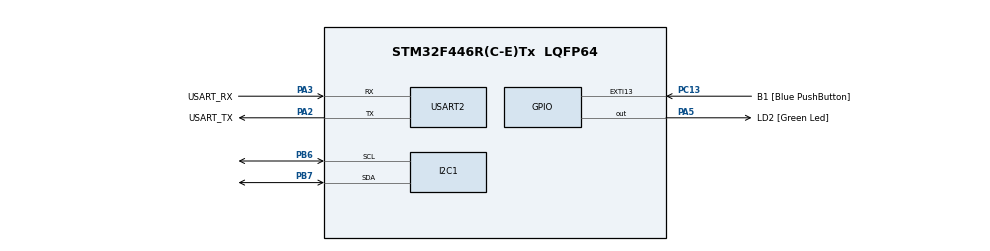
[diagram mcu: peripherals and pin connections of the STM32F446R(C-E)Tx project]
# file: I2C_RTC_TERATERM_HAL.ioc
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Mcu.Family=STM32F4
Mcu.Name=STM32F446R(C-E)Tx
Mcu.Package=LQFP64
NVIC.PriorityGroup=NVIC_PRIORITYGROUP_0
PA13.GPIO_Label=TMS
PA13.Mode=Serial_Wire
PA13.Signal=SYS_JTMS-SWDIO
PA14.GPIO_Label=TCK
PA14.Mode=Serial_Wire
PA14.Signal=SYS_JTCK-SWCLK
PA2.GPIO_Label=USART_TX
PA2.Mode=Asynchronous
PA2.Signal=USART2_TX
PA3.GPIO_Label=USART_RX
PA3.Mode=Asynchronous
PA3.Signal=USART2_RX
PA5.GPIO_Label=LD2 [Green Led]
PA5.Signal=GPIO_Output
PB3.GPIO_Label=SWO
PB3.Signal=SYS_JTDO-SWO
PB6.Mode=I2C
PB6.Signal=I2C1_SCL
PB7.Mode=I2C
PB7.Signal=I2C1_SDA
PC13.GPIO_Label=B1 [Blue PushButton]
PC13.GPIO_ModeDefaultEXTI=GPIO_MODE_IT_FALLING
PC13.Signal=GPXTI13
PC14-OSC32_IN.Mode=LSE-External-Oscillator
PC14-OSC32_IN.Signal=RCC_OSC32_IN
PC15-OSC32_OUT.Mode=LSE-External-Oscillator
PC15-OSC32_OUT.Signal=RCC_OSC32_OUT
PH0-OSC_IN.Mode=HSE-External-Oscillator
PH0-OSC_IN.Signal=RCC_OSC_IN
PH1-OSC_OUT.Mode=HSE-External-Oscillator
PH1-OSC_OUT.Signal=RCC_OSC_OUT
ProjectManager.HeapSize=0x200
ProjectManager.StackSize=0x400
ProjectManager.TargetToolchain=STM32CubeIDE
RCC.48MHZClocksFreq_Value=84000000
RCC.AHBFreq_Value=16000000
RCC.APB1CLKDivider=RCC_HCLK_DIV2
RCC.APB1Freq_Value=8000000
RCC.APB1TimFreq_Value=16000000
RCC.APB2Freq_Value=16000000
RCC.APB2TimFreq_Value=16000000
RCC.CortexFreq_Value=16000000
RCC.FLatency-AdvancedSettings=FLASH_LATENCY_0
RCC.HCLKFreq_Value=16000000
RCC.HSE_VALUE=8000000
RCC.HSI_VALUE=16000000
RCC.PLLN=336
RCC.PLLP=RCC_PLLP_DIV4
RCC.SYSCLKFreq_VALUE=16000000
RCC.USBFreq_Value=168000000
RCC.VCOOutputFreq_Value=336000000
USART2.VirtualMode=VM_ASYNC
board=NUCLEO-F446RE

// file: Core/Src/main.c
/* USER CODE BEGIN Header */
/**
  ******************************************************************************
  * @file           : main.c
  * @brief          : Main program body
  ******************************************************************************
  * @attention
  *
  * Copyright (c) 2026 STMicroelectronics.
  * All rights reserved.
  *
  * This software is licensed under terms that can be found in the LICENSE file
  * in the root directory of this software component.
  * If no LICENSE file comes with this software, it is provided AS-IS.
  *
  ******************************************************************************
  */
/* USER CODE END Header */

#include "main.h"
#include <stdio.h>
#include <string.h>

I2C_HandleTypeDef hi2c1;
UART_HandleTypeDef huart2;

/* USER CODE BEGIN PV */
#define DS1307_ADDR (0x68 << 1)

uint8_t sec, min, hour;
uint8_t day, date, month, year;
/* USER CODE END PV */

/* USER CODE BEGIN 0 */
uint8_t DecToBCD(uint8_t val) {
    return ((val / 10) << 4) | (val % 10);
}

uint8_t BCDToDec(uint8_t val) {
    return ((val >> 4) * 10) + (val & 0x0F);
}

void DS1307_SetTime(uint8_t sec, uint8_t min, uint8_t hour,
                    uint8_t day, uint8_t date, uint8_t month, uint8_t year) {
    uint8_t rtc_data[7];
    rtc_data[0] = DecToBCD(sec);
    rtc_data[1] = DecToBCD(min);
    rtc_data[2] = DecToBCD(hour);
    rtc_data[3] = DecToBCD(day);
    rtc_data[4] = DecToBCD(date);
    rtc_data[5] = DecToBCD(month);
    rtc_data[6] = DecToBCD(year);

    HAL_I2C_Mem_Write(&hi2c1, DS1307_ADDR, 0x00,
                      I2C_MEMADD_SIZE_8BIT, rtc_data, 7, HAL_MAX_DELAY);
}

void DS1307_ReadTime(void) {
    uint8_t rtc_data[7];
    HAL_I2C_Mem_Read(&hi2c1, DS1307_ADDR, 0x00,
                     I2C_MEMADD_SIZE_8BIT, rtc_data, 7, HAL_MAX_DELAY);

    sec   = BCDToDec(rtc_data[0] & 0x7F);
    min   = BCDToDec(rtc_data[1]);
    hour  = BCDToDec(rtc_data[2] & 0x3F);
    day   = BCDToDec(rtc_data[3]);
    date  = BCDToDec(rtc_data[4]);
    month = BCDToDec(rtc_data[5]);
    year  = BCDToDec(rtc_data[6]);
}
/* USER CODE END 0 */

void SystemClock_Config(void);
static void MX_GPIO_Init(void);
static void MX_USART2_UART_Init(void);
static void MX_I2C1_Init(void);

int main(void) {
  HAL_Init();
  SystemClock_Config();
  MX_GPIO_Init();
  MX_USART2_UART_Init();
  MX_I2C1_Init();

  /* USER CODE BEGIN 2 */
  // ⚠️ Call once to set RTC, then comment out
  // DS1307_SetTime(0, 30, 12, 5, 11, 6, 26);
  /* USER CODE END 2 */

  while (1) {
    /* USER CODE BEGIN WHILE */
    DS1307_ReadTime();

    char msg[100];
    sprintf(msg, "Time: %02d:%02d:%02d  Date: %02d/%02d/20%02d  Day:%d\r\n",
            hour, min, sec, date, month, year, day);

    HAL_UART_Transmit(&huart2, (uint8_t*)msg, strlen(msg), HAL_MAX_DELAY);
    HAL_Delay(1000);
    /* USER CODE END WHILE */
  }
}

void SystemClock_Config(void) {
  RCC_OscInitTypeDef RCC_OscInitStruct = {0};
  RCC_ClkInitTypeDef RCC_ClkInitStruct = {0};

  __HAL_RCC_PWR_CLK_ENABLE();
  __HAL_PWR_VOLTAGESCALING_CONFIG(PWR_REGULATOR_VOLTAGE_SCALE1);

  RCC_OscInitStruct.OscillatorType = RCC_OSCILLATORTYPE_HSI;
  RCC_OscInitStruct.HSIState = RCC_HSI_ON;
  RCC_OscInitStruct.HSICalibrationValue = RCC_HSICALIBRATION_DEFAULT;
  RCC_OscInitStruct.PLL.PLLState = RCC_PLL_ON;
  RCC_OscInitStruct.PLL.PLLSource = RCC_PLLSOURCE_HSI;
  RCC_OscInitStruct.PLL.PLLM = 16;
  RCC_OscInitStruct.PLL.PLLN = 336;
  RCC_OscInitStruct.PLL.PLLP = RCC_PLLP_DIV4;
  RCC_OscInitStruct.PLL.PLLQ = 4;
  if (HAL_RCC_OscConfig(&RCC_OscInitStruct) != HAL_OK) {
    Error_Handler();
  }

  RCC_ClkInitStruct.ClockType = RCC_CLOCKTYPE_HCLK|RCC_CLOCKTYPE_SYSCLK
                              |RCC_CLOCKTYPE_PCLK1|RCC_CLOCKTYPE_PCLK2;
  RCC_ClkInitStruct.SYSCLKSource = RCC_SYSCLKSOURCE_PLLCLK;
  RCC_ClkInitStruct.AHBCLKDivider = RCC_SYSCLK_DIV1;
  RCC_ClkInitStruct.APB1CLKDivider = RCC_HCLK_DIV2;
  RCC_ClkInitStruct.APB2CLKDivider = RCC_HCLK_DIV1;

  if (HAL_RCC_ClockConfig(&RCC_ClkInitStruct, FLASH_LATENCY_2) != HAL_OK) {
    Error_Handler();
  }
}

static void MX_I2C1_Init(void) {
  hi2c1.Instance = I2C1;
  hi2c1.Init.ClockSpeed = 100000;
  hi2c1.Init.DutyCycle = I2C_DUTYCYCLE_2;
  hi2c1.Init.OwnAddress1 = 0;
  hi2c1.Init.AddressingMode = I2C_ADDRESSINGMODE_7BIT;
  hi2c1.Init.DualAddressMode = I2C_DUALADDRESS_DISABLE;
  hi2c1.Init.OwnAddress2 = 0;
  hi2c1.Init.GeneralCallMode = I2C_GENERALCALL_DISABLE;
  hi2c1.Init.NoStretchMode = I2C_NOSTRETCH_DISABLE;
  if (HAL_I2C_Init(&hi2c1) != HAL_OK) {
    Error_Handler();
  }
}

static void MX_USART2_UART_Init(void) {
  huart2.Instance = USART2;
  huart2.Init.BaudRate = 115200;
  huart2.Init.WordLength = UART_WORDLENGTH_8B;
  huart2.Init.StopBits = UART_STOPBITS_1;
  huart2.Init.Parity = UART_PARITY_NONE;
  huart2.Init.Mode = UART_MODE_TX_RX;
  huart2.Init.HwFlowCtl = UART_HWCONTROL_NONE;
  huart2.Init.OverSampling = UART_OVERSAMPLING_16;
  if (HAL_UART_Init(&huart2) != HAL_OK) {
    Error_Handler();
  }
}

static void MX_GPIO_Init(void) {
  GPIO_InitTypeDef GPIO_InitStruct = {0};

  __HAL_RCC_GPIOC_CLK_ENABLE();
  __HAL_RCC_GPIOH_CLK_ENABLE();
  __HAL_RCC_GPIOA_CLK_ENABLE();
  __HAL_RCC_GPIOB_CLK_ENABLE();

  HAL_GPIO_WritePin(LD2_GPIO_Port, LD2_Pin, GPIO_PIN_RESET);

  GPIO_InitStruct.Pin = B1_Pin;
  GPIO_InitStruct.Mode = GPIO_MODE_IT_FALLING;
  GPIO_InitStruct.Pull = GPIO_NOPULL;
  HAL_GPIO_Init(B1_GPIO_Port, &GPIO_InitStruct);

  GPIO_InitStruct.Pin = LD2_Pin;
  GPIO_InitStruct.Mode = GPIO_MODE_OUTPUT_PP;
  GPIO_InitStruct.Pull = GPIO_NOPULL;
  GPIO_InitStruct.Speed = GPIO_SPEED_FREQ_LOW;
  HAL_GPIO_Init(LD2_GPIO_Port, &GPIO_InitStruct);
}

void Error_Handler(void) {
  __disable_irq();
  while (1) {
  }
}
